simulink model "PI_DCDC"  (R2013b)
settings: Solver=FixedStepDiscrete  StartTime=0.0  StopTime=0.02  FixedStep=2e-5  RelTol=1e-3
libraries: CONNECT_BLOCKS_13 x1

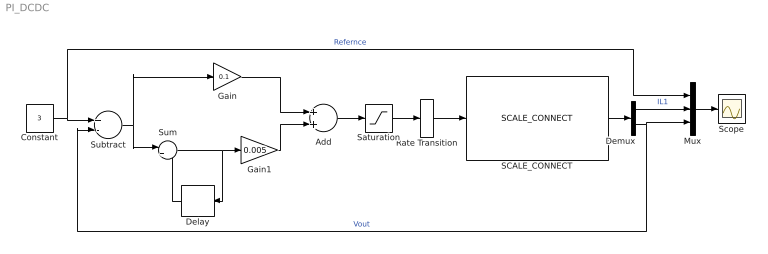
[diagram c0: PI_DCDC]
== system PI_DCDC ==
  Add : Sum
  Constant : Constant  Value=3
  Delay : Delay  DelayLength=1  InitialCondition=0
  Demux : Demux  Outputs=2
  Gain : Gain  Gain=0.1
  Gain1 : Gain  Gain=0.005
  Mux : Mux  Inputs=3
  Rate Transition : RateTransition  OutPortSampleTime=2e-5
  SCALE_CONNECT : CONNECT_BLOCKS_13/SCALE_CONNECT  Path=[]  FileName=C:\Users\shotasuzuki\Desktop\working\ModelsSCALEConnectTutorial\ModelsSCALEConnectTutorial\BuckConverter.cvt2  ForkOption=自動起動  FileChangeFlag=on  DisposeRequirementFlag=off  SimulationMode=Transient  WaveformStartTime=0  FrequencyResponseAnalysisStartTime=0  InputWidth=1  OutputWidth=2
  Saturation : Saturate  UpperLimit=1  LowerLimit=0
  Scope : Scope
  Subtract : Sum  Inputs=+-
  Sum : Sum  Inputs=|++
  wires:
  Constant/1 -> Mux/1, Subtract/1  "Refernce"
  Rate Transition/1 -> SCALE_CONNECT/1
  SCALE_CONNECT/1 -> Demux/1
  Subtract/1 -> Gain/1, Sum/1
  Gain/1 -> Add/1
  Add/1 -> Saturation/1
  Gain1/1 -> Add/2
  Sum/1 -> Delay/1, Gain1/1
  Delay/1 -> Sum/2
  Mux/1 -> Scope/1
  Saturation/1 -> Rate Transition/1
  Demux/1 -> Mux/2  "IL1"
  Demux/2 -> Mux/3, Subtract/2  "Vout"
